# Generated by FakeRAM 2.0
VERSION 5.7 ;
BUSBITCHARS "[]" ;
PROPERTYDEFINITIONS
  MACRO width INTEGER ;
  MACRO depth INTEGER ;
  MACRO banks INTEGER ;
END PROPERTYDEFINITIONS
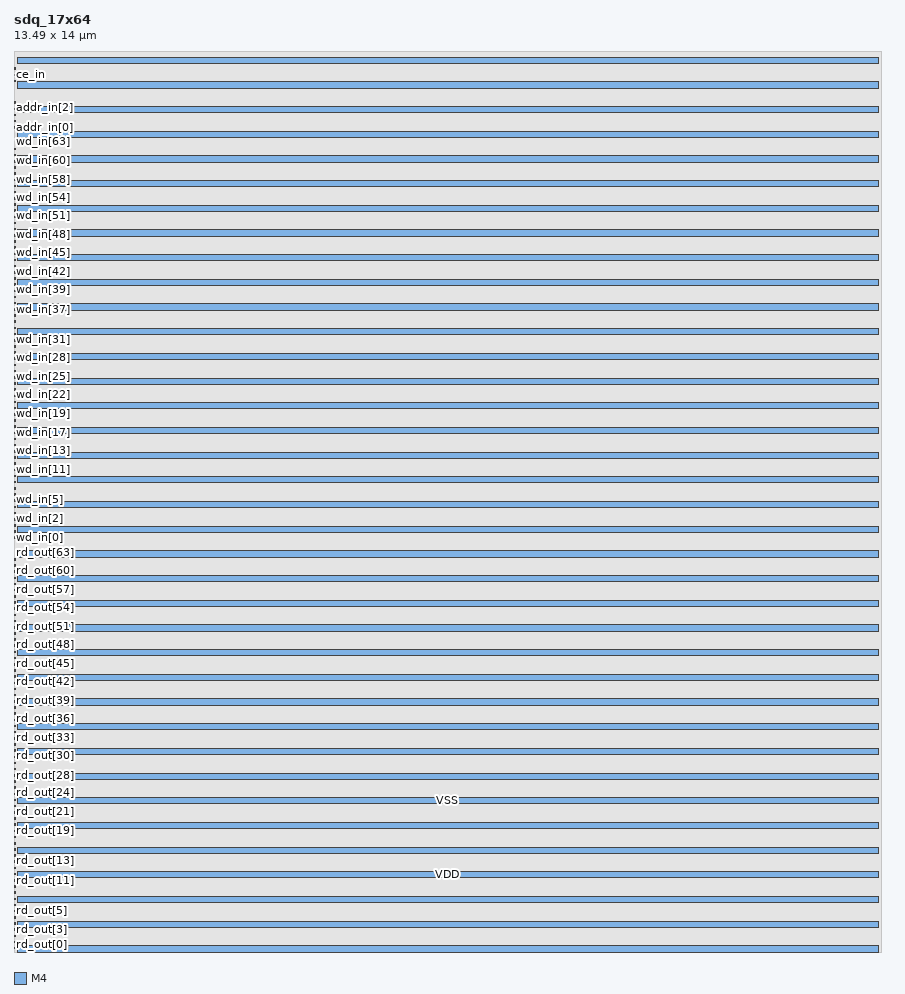
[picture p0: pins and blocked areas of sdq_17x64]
MACRO sdq_17x64
  PROPERTY width 64 ;
  PROPERTY depth 17 ;
  PROPERTY banks 1 ;
  FOREIGN sdq_17x64 0 0 ;
  SYMMETRY X Y R90 ;
  SIZE 13.490 BY 14.000 ;
  CLASS BLOCK ;
  PIN rd_out[0]
    DIRECTION OUTPUT ;
    USE SIGNAL ;
    SHAPE ABUTMENT ;
    PORT
      LAYER M4 ;
      RECT 0.000 0.048 0.024 0.072 ;
    END
  END rd_out[0]
  PIN rd_out[1]
    DIRECTION OUTPUT ;
    USE SIGNAL ;
    SHAPE ABUTMENT ;
    PORT
      LAYER M4 ;
      RECT 0.000 0.144 0.024 0.168 ;
    END
  END rd_out[1]
  PIN rd_out[2]
    DIRECTION OUTPUT ;
    USE SIGNAL ;
    SHAPE ABUTMENT ;
    PORT
      LAYER M4 ;
      RECT 0.000 0.240 0.024 0.264 ;
    END
  END rd_out[2]
  PIN rd_out[3]
    DIRECTION OUTPUT ;
    USE SIGNAL ;
    SHAPE ABUTMENT ;
    PORT
      LAYER M4 ;
      RECT 0.000 0.336 0.024 0.360 ;
    END
  END rd_out[3]
  PIN rd_out[4]
    DIRECTION OUTPUT ;
    USE SIGNAL ;
    SHAPE ABUTMENT ;
    PORT
      LAYER M4 ;
      RECT 0.000 0.432 0.024 0.456 ;
    END
  END rd_out[4]
  PIN rd_out[5]
    DIRECTION OUTPUT ;
    USE SIGNAL ;
    SHAPE ABUTMENT ;
    PORT
      LAYER M4 ;
      RECT 0.000 0.528 0.024 0.552 ;
    END
  END rd_out[5]
  PIN rd_out[6]
    DIRECTION OUTPUT ;
    USE SIGNAL ;
    SHAPE ABUTMENT ;
    PORT
      LAYER M4 ;
      RECT 0.000 0.624 0.024 0.648 ;
    END
  END rd_out[6]
  PIN rd_out[7]
    DIRECTION OUTPUT ;
    USE SIGNAL ;
    SHAPE ABUTMENT ;
    PORT
      LAYER M4 ;
      RECT 0.000 0.720 0.024 0.744 ;
    END
  END rd_out[7]
  PIN rd_out[8]
    DIRECTION OUTPUT ;
    USE SIGNAL ;
    SHAPE ABUTMENT ;
    PORT
      LAYER M4 ;
      RECT 0.000 0.816 0.024 0.840 ;
    END
  END rd_out[8]
  PIN rd_out[9]
    DIRECTION OUTPUT ;
    USE SIGNAL ;
    SHAPE ABUTMENT ;
    PORT
      LAYER M4 ;
      RECT 0.000 0.912 0.024 0.936 ;
    END
  END rd_out[9]
  PIN rd_out[10]
    DIRECTION OUTPUT ;
    USE SIGNAL ;
    SHAPE ABUTMENT ;
    PORT
      LAYER M4 ;
      RECT 0.000 1.008 0.024 1.032 ;
    END
  END rd_out[10]
  PIN rd_out[11]
    DIRECTION OUTPUT ;
    USE SIGNAL ;
    SHAPE ABUTMENT ;
    PORT
      LAYER M4 ;
      RECT 0.000 1.104 0.024 1.128 ;
    END
  END rd_out[11]
  PIN rd_out[12]
    DIRECTION OUTPUT ;
    USE SIGNAL ;
    SHAPE ABUTMENT ;
    PORT
      LAYER M4 ;
      RECT 0.000 1.200 0.024 1.224 ;
    END
  END rd_out[12]
  PIN rd_out[13]
    DIRECTION OUTPUT ;
    USE SIGNAL ;
    SHAPE ABUTMENT ;
    PORT
      LAYER M4 ;
      RECT 0.000 1.296 0.024 1.320 ;
    END
  END rd_out[13]
  PIN rd_out[14]
    DIRECTION OUTPUT ;
    USE SIGNAL ;
    SHAPE ABUTMENT ;
    PORT
      LAYER M4 ;
      RECT 0.000 1.392 0.024 1.416 ;
    END
  END rd_out[14]
  PIN rd_out[15]
    DIRECTION OUTPUT ;
    USE SIGNAL ;
    SHAPE ABUTMENT ;
    PORT
      LAYER M4 ;
      RECT 0.000 1.488 0.024 1.512 ;
    END
  END rd_out[15]
  PIN rd_out[16]
    DIRECTION OUTPUT ;
    USE SIGNAL ;
    SHAPE ABUTMENT ;
    PORT
      LAYER M4 ;
      RECT 0.000 1.584 0.024 1.608 ;
    END
  END rd_out[16]
  PIN rd_out[17]
    DIRECTION OUTPUT ;
    USE SIGNAL ;
    SHAPE ABUTMENT ;
    PORT
      LAYER M4 ;
      RECT 0.000 1.680 0.024 1.704 ;
    END
  END rd_out[17]
  PIN rd_out[18]
    DIRECTION OUTPUT ;
    USE SIGNAL ;
    SHAPE ABUTMENT ;
    PORT
      LAYER M4 ;
      RECT 0.000 1.776 0.024 1.800 ;
    END
  END rd_out[18]
  PIN rd_out[19]
    DIRECTION OUTPUT ;
    USE SIGNAL ;
    SHAPE ABUTMENT ;
    PORT
      LAYER M4 ;
      RECT 0.000 1.872 0.024 1.896 ;
    END
  END rd_out[19]
  PIN rd_out[20]
    DIRECTION OUTPUT ;
    USE SIGNAL ;
    SHAPE ABUTMENT ;
    PORT
      LAYER M4 ;
      RECT 0.000 1.968 0.024 1.992 ;
    END
  END rd_out[20]
  PIN rd_out[21]
    DIRECTION OUTPUT ;
    USE SIGNAL ;
    SHAPE ABUTMENT ;
    PORT
      LAYER M4 ;
      RECT 0.000 2.064 0.024 2.088 ;
    END
  END rd_out[21]
  PIN rd_out[22]
    DIRECTION OUTPUT ;
    USE SIGNAL ;
    SHAPE ABUTMENT ;
    PORT
      LAYER M4 ;
      RECT 0.000 2.160 0.024 2.184 ;
    END
  END rd_out[22]
  PIN rd_out[23]
    DIRECTION OUTPUT ;
    USE SIGNAL ;
    SHAPE ABUTMENT ;
    PORT
      LAYER M4 ;
      RECT 0.000 2.256 0.024 2.280 ;
    END
  END rd_out[23]
  PIN rd_out[24]
    DIRECTION OUTPUT ;
    USE SIGNAL ;
    SHAPE ABUTMENT ;
    PORT
      LAYER M4 ;
      RECT 0.000 2.352 0.024 2.376 ;
    END
  END rd_out[24]
  PIN rd_out[25]
    DIRECTION OUTPUT ;
    USE SIGNAL ;
    SHAPE ABUTMENT ;
    PORT
      LAYER M4 ;
      RECT 0.000 2.448 0.024 2.472 ;
    END
  END rd_out[25]
  PIN rd_out[26]
    DIRECTION OUTPUT ;
    USE SIGNAL ;
    SHAPE ABUTMENT ;
    PORT
      LAYER M4 ;
      RECT 0.000 2.544 0.024 2.568 ;
    END
  END rd_out[26]
  PIN rd_out[27]
    DIRECTION OUTPUT ;
    USE SIGNAL ;
    SHAPE ABUTMENT ;
    PORT
      LAYER M4 ;
      RECT 0.000 2.640 0.024 2.664 ;
    END
  END rd_out[27]
  PIN rd_out[28]
    DIRECTION OUTPUT ;
    USE SIGNAL ;
    SHAPE ABUTMENT ;
    PORT
      LAYER M4 ;
      RECT 0.000 2.736 0.024 2.760 ;
    END
  END rd_out[28]
  PIN rd_out[29]
    DIRECTION OUTPUT ;
    USE SIGNAL ;
    SHAPE ABUTMENT ;
    PORT
      LAYER M4 ;
      RECT 0.000 2.832 0.024 2.856 ;
    END
  END rd_out[29]
  PIN rd_out[30]
    DIRECTION OUTPUT ;
    USE SIGNAL ;
    SHAPE ABUTMENT ;
    PORT
      LAYER M4 ;
      RECT 0.000 2.928 0.024 2.952 ;
    END
  END rd_out[30]
  PIN rd_out[31]
    DIRECTION OUTPUT ;
    USE SIGNAL ;
    SHAPE ABUTMENT ;
    PORT
      LAYER M4 ;
      RECT 0.000 3.024 0.024 3.048 ;
    END
  END rd_out[31]
  PIN rd_out[32]
    DIRECTION OUTPUT ;
    USE SIGNAL ;
    SHAPE ABUTMENT ;
    PORT
      LAYER M4 ;
      RECT 0.000 3.120 0.024 3.144 ;
    END
  END rd_out[32]
  PIN rd_out[33]
    DIRECTION OUTPUT ;
    USE SIGNAL ;
    SHAPE ABUTMENT ;
    PORT
      LAYER M4 ;
      RECT 0.000 3.216 0.024 3.240 ;
    END
  END rd_out[33]
  PIN rd_out[34]
    DIRECTION OUTPUT ;
    USE SIGNAL ;
    SHAPE ABUTMENT ;
    PORT
      LAYER M4 ;
      RECT 0.000 3.312 0.024 3.336 ;
    END
  END rd_out[34]
  PIN rd_out[35]
    DIRECTION OUTPUT ;
    USE SIGNAL ;
    SHAPE ABUTMENT ;
    PORT
      LAYER M4 ;
      RECT 0.000 3.408 0.024 3.432 ;
    END
  END rd_out[35]
  PIN rd_out[36]
    DIRECTION OUTPUT ;
    USE SIGNAL ;
    SHAPE ABUTMENT ;
    PORT
      LAYER M4 ;
      RECT 0.000 3.504 0.024 3.528 ;
    END
  END rd_out[36]
  PIN rd_out[37]
    DIRECTION OUTPUT ;
    USE SIGNAL ;
    SHAPE ABUTMENT ;
    PORT
      LAYER M4 ;
      RECT 0.000 3.600 0.024 3.624 ;
    END
  END rd_out[37]
  PIN rd_out[38]
    DIRECTION OUTPUT ;
    USE SIGNAL ;
    SHAPE ABUTMENT ;
    PORT
      LAYER M4 ;
      RECT 0.000 3.696 0.024 3.720 ;
    END
  END rd_out[38]
  PIN rd_out[39]
    DIRECTION OUTPUT ;
    USE SIGNAL ;
    SHAPE ABUTMENT ;
    PORT
      LAYER M4 ;
      RECT 0.000 3.792 0.024 3.816 ;
    END
  END rd_out[39]
  PIN rd_out[40]
    DIRECTION OUTPUT ;
    USE SIGNAL ;
    SHAPE ABUTMENT ;
    PORT
      LAYER M4 ;
      RECT 0.000 3.888 0.024 3.912 ;
    END
  END rd_out[40]
  PIN rd_out[41]
    DIRECTION OUTPUT ;
    USE SIGNAL ;
    SHAPE ABUTMENT ;
    PORT
      LAYER M4 ;
      RECT 0.000 3.984 0.024 4.008 ;
    END
  END rd_out[41]
  PIN rd_out[42]
    DIRECTION OUTPUT ;
    USE SIGNAL ;
    SHAPE ABUTMENT ;
    PORT
      LAYER M4 ;
      RECT 0.000 4.080 0.024 4.104 ;
    END
  END rd_out[42]
  PIN rd_out[43]
    DIRECTION OUTPUT ;
    USE SIGNAL ;
    SHAPE ABUTMENT ;
    PORT
      LAYER M4 ;
      RECT 0.000 4.176 0.024 4.200 ;
    END
  END rd_out[43]
  PIN rd_out[44]
    DIRECTION OUTPUT ;
    USE SIGNAL ;
    SHAPE ABUTMENT ;
    PORT
      LAYER M4 ;
      RECT 0.000 4.272 0.024 4.296 ;
    END
  END rd_out[44]
  PIN rd_out[45]
    DIRECTION OUTPUT ;
    USE SIGNAL ;
    SHAPE ABUTMENT ;
    PORT
      LAYER M4 ;
      RECT 0.000 4.368 0.024 4.392 ;
    END
  END rd_out[45]
  PIN rd_out[46]
    DIRECTION OUTPUT ;
    USE SIGNAL ;
    SHAPE ABUTMENT ;
    PORT
      LAYER M4 ;
      RECT 0.000 4.464 0.024 4.488 ;
    END
  END rd_out[46]
  PIN rd_out[47]
    DIRECTION OUTPUT ;
    USE SIGNAL ;
    SHAPE ABUTMENT ;
    PORT
      LAYER M4 ;
      RECT 0.000 4.560 0.024 4.584 ;
    END
  END rd_out[47]
  PIN rd_out[48]
    DIRECTION OUTPUT ;
    USE SIGNAL ;
    SHAPE ABUTMENT ;
    PORT
      LAYER M4 ;
      RECT 0.000 4.656 0.024 4.680 ;
    END
  END rd_out[48]
  PIN rd_out[49]
    DIRECTION OUTPUT ;
    USE SIGNAL ;
    SHAPE ABUTMENT ;
    PORT
      LAYER M4 ;
      RECT 0.000 4.752 0.024 4.776 ;
    END
  END rd_out[49]
  PIN rd_out[50]
    DIRECTION OUTPUT ;
    USE SIGNAL ;
    SHAPE ABUTMENT ;
    PORT
      LAYER M4 ;
      RECT 0.000 4.848 0.024 4.872 ;
    END
  END rd_out[50]
  PIN rd_out[51]
    DIRECTION OUTPUT ;
    USE SIGNAL ;
    SHAPE ABUTMENT ;
    PORT
      LAYER M4 ;
      RECT 0.000 4.944 0.024 4.968 ;
    END
  END rd_out[51]
  PIN rd_out[52]
    DIRECTION OUTPUT ;
    USE SIGNAL ;
    SHAPE ABUTMENT ;
    PORT
      LAYER M4 ;
      RECT 0.000 5.040 0.024 5.064 ;
    END
  END rd_out[52]
  PIN rd_out[53]
    DIRECTION OUTPUT ;
    USE SIGNAL ;
    SHAPE ABUTMENT ;
    PORT
      LAYER M4 ;
      RECT 0.000 5.136 0.024 5.160 ;
    END
  END rd_out[53]
  PIN rd_out[54]
    DIRECTION OUTPUT ;
    USE SIGNAL ;
    SHAPE ABUTMENT ;
    PORT
      LAYER M4 ;
      RECT 0.000 5.232 0.024 5.256 ;
    END
  END rd_out[54]
  PIN rd_out[55]
    DIRECTION OUTPUT ;
    USE SIGNAL ;
    SHAPE ABUTMENT ;
    PORT
      LAYER M4 ;
      RECT 0.000 5.328 0.024 5.352 ;
    END
  END rd_out[55]
  PIN rd_out[56]
    DIRECTION OUTPUT ;
    USE SIGNAL ;
    SHAPE ABUTMENT ;
    PORT
      LAYER M4 ;
      RECT 0.000 5.424 0.024 5.448 ;
    END
  END rd_out[56]
  PIN rd_out[57]
    DIRECTION OUTPUT ;
    USE SIGNAL ;
    SHAPE ABUTMENT ;
    PORT
      LAYER M4 ;
      RECT 0.000 5.520 0.024 5.544 ;
    END
  END rd_out[57]
  PIN rd_out[58]
    DIRECTION OUTPUT ;
    USE SIGNAL ;
    SHAPE ABUTMENT ;
    PORT
      LAYER M4 ;
      RECT 0.000 5.616 0.024 5.640 ;
    END
  END rd_out[58]
  PIN rd_out[59]
    DIRECTION OUTPUT ;
    USE SIGNAL ;
    SHAPE ABUTMENT ;
    PORT
      LAYER M4 ;
      RECT 0.000 5.712 0.024 5.736 ;
    END
  END rd_out[59]
  PIN rd_out[60]
    DIRECTION OUTPUT ;
    USE SIGNAL ;
    SHAPE ABUTMENT ;
    PORT
      LAYER M4 ;
      RECT 0.000 5.808 0.024 5.832 ;
    END
  END rd_out[60]
  PIN rd_out[61]
    DIRECTION OUTPUT ;
    USE SIGNAL ;
    SHAPE ABUTMENT ;
    PORT
      LAYER M4 ;
      RECT 0.000 5.904 0.024 5.928 ;
    END
  END rd_out[61]
  PIN rd_out[62]
    DIRECTION OUTPUT ;
    USE SIGNAL ;
    SHAPE ABUTMENT ;
    PORT
      LAYER M4 ;
      RECT 0.000 6.000 0.024 6.024 ;
    END
  END rd_out[62]
  PIN rd_out[63]
    DIRECTION OUTPUT ;
    USE SIGNAL ;
    SHAPE ABUTMENT ;
    PORT
      LAYER M4 ;
      RECT 0.000 6.096 0.024 6.120 ;
    END
  END rd_out[63]
  PIN wd_in[0]
    DIRECTION INPUT ;
    USE SIGNAL ;
    SHAPE ABUTMENT ;
    PORT
      LAYER M4 ;
      RECT 0.000 6.432 0.024 6.456 ;
    END
  END wd_in[0]
  PIN wd_in[1]
    DIRECTION INPUT ;
    USE SIGNAL ;
    SHAPE ABUTMENT ;
    PORT
      LAYER M4 ;
      RECT 0.000 6.528 0.024 6.552 ;
    END
  END wd_in[1]
  PIN wd_in[2]
    DIRECTION INPUT ;
    USE SIGNAL ;
    SHAPE ABUTMENT ;
    PORT
      LAYER M4 ;
      RECT 0.000 6.624 0.024 6.648 ;
    END
  END wd_in[2]
  PIN wd_in[3]
    DIRECTION INPUT ;
    USE SIGNAL ;
    SHAPE ABUTMENT ;
    PORT
      LAYER M4 ;
      RECT 0.000 6.720 0.024 6.744 ;
    END
  END wd_in[3]
  PIN wd_in[4]
    DIRECTION INPUT ;
    USE SIGNAL ;
    SHAPE ABUTMENT ;
    PORT
      LAYER M4 ;
      RECT 0.000 6.816 0.024 6.840 ;
    END
  END wd_in[4]
  PIN wd_in[5]
    DIRECTION INPUT ;
    USE SIGNAL ;
    SHAPE ABUTMENT ;
    PORT
      LAYER M4 ;
      RECT 0.000 6.912 0.024 6.936 ;
    END
  END wd_in[5]
  PIN wd_in[6]
    DIRECTION INPUT ;
    USE SIGNAL ;
    SHAPE ABUTMENT ;
    PORT
      LAYER M4 ;
      RECT 0.000 7.008 0.024 7.032 ;
    END
  END wd_in[6]
  PIN wd_in[7]
    DIRECTION INPUT ;
    USE SIGNAL ;
    SHAPE ABUTMENT ;
    PORT
      LAYER M4 ;
      RECT 0.000 7.104 0.024 7.128 ;
    END
  END wd_in[7]
  PIN wd_in[8]
    DIRECTION INPUT ;
    USE SIGNAL ;
    SHAPE ABUTMENT ;
    PORT
      LAYER M4 ;
      RECT 0.000 7.200 0.024 7.224 ;
    END
  END wd_in[8]
  PIN wd_in[9]
    DIRECTION INPUT ;
    USE SIGNAL ;
    SHAPE ABUTMENT ;
    PORT
      LAYER M4 ;
      RECT 0.000 7.296 0.024 7.320 ;
    END
  END wd_in[9]
  PIN wd_in[10]
    DIRECTION INPUT ;
    USE SIGNAL ;
    SHAPE ABUTMENT ;
    PORT
      LAYER M4 ;
      RECT 0.000 7.392 0.024 7.416 ;
    END
  END wd_in[10]
  PIN wd_in[11]
    DIRECTION INPUT ;
    USE SIGNAL ;
    SHAPE ABUTMENT ;
    PORT
      LAYER M4 ;
      RECT 0.000 7.488 0.024 7.512 ;
    END
  END wd_in[11]
  PIN wd_in[12]
    DIRECTION INPUT ;
    USE SIGNAL ;
    SHAPE ABUTMENT ;
    PORT
      LAYER M4 ;
      RECT 0.000 7.584 0.024 7.608 ;
    END
  END wd_in[12]
  PIN wd_in[13]
    DIRECTION INPUT ;
    USE SIGNAL ;
    SHAPE ABUTMENT ;
    PORT
      LAYER M4 ;
      RECT 0.000 7.680 0.024 7.704 ;
    END
  END wd_in[13]
  PIN wd_in[14]
    DIRECTION INPUT ;
    USE SIGNAL ;
    SHAPE ABUTMENT ;
    PORT
      LAYER M4 ;
      RECT 0.000 7.776 0.024 7.800 ;
    END
  END wd_in[14]
  PIN wd_in[15]
    DIRECTION INPUT ;
    USE SIGNAL ;
    SHAPE ABUTMENT ;
    PORT
      LAYER M4 ;
      RECT 0.000 7.872 0.024 7.896 ;
    END
  END wd_in[15]
  PIN wd_in[16]
    DIRECTION INPUT ;
    USE SIGNAL ;
    SHAPE ABUTMENT ;
    PORT
      LAYER M4 ;
      RECT 0.000 7.968 0.024 7.992 ;
    END
  END wd_in[16]
  PIN wd_in[17]
    DIRECTION INPUT ;
    USE SIGNAL ;
    SHAPE ABUTMENT ;
    PORT
      LAYER M4 ;
      RECT 0.000 8.064 0.024 8.088 ;
    END
  END wd_in[17]
  PIN wd_in[18]
    DIRECTION INPUT ;
    USE SIGNAL ;
    SHAPE ABUTMENT ;
    PORT
      LAYER M4 ;
      RECT 0.000 8.160 0.024 8.184 ;
    END
  END wd_in[18]
  PIN wd_in[19]
    DIRECTION INPUT ;
    USE SIGNAL ;
    SHAPE ABUTMENT ;
    PORT
      LAYER M4 ;
      RECT 0.000 8.256 0.024 8.280 ;
    END
  END wd_in[19]
  PIN wd_in[20]
    DIRECTION INPUT ;
    USE SIGNAL ;
    SHAPE ABUTMENT ;
    PORT
      LAYER M4 ;
      RECT 0.000 8.352 0.024 8.376 ;
    END
  END wd_in[20]
  PIN wd_in[21]
    DIRECTION INPUT ;
    USE SIGNAL ;
    SHAPE ABUTMENT ;
    PORT
      LAYER M4 ;
      RECT 0.000 8.448 0.024 8.472 ;
    END
  END wd_in[21]
  PIN wd_in[22]
    DIRECTION INPUT ;
    USE SIGNAL ;
    SHAPE ABUTMENT ;
    PORT
      LAYER M4 ;
      RECT 0.000 8.544 0.024 8.568 ;
    END
  END wd_in[22]
  PIN wd_in[23]
    DIRECTION INPUT ;
    USE SIGNAL ;
    SHAPE ABUTMENT ;
    PORT
      LAYER M4 ;
      RECT 0.000 8.640 0.024 8.664 ;
    END
  END wd_in[23]
  PIN wd_in[24]
    DIRECTION INPUT ;
    USE SIGNAL ;
    SHAPE ABUTMENT ;
    PORT
      LAYER M4 ;
      RECT 0.000 8.736 0.024 8.760 ;
    END
  END wd_in[24]
  PIN wd_in[25]
    DIRECTION INPUT ;
    USE SIGNAL ;
    SHAPE ABUTMENT ;
    PORT
      LAYER M4 ;
      RECT 0.000 8.832 0.024 8.856 ;
    END
  END wd_in[25]
  PIN wd_in[26]
    DIRECTION INPUT ;
    USE SIGNAL ;
    SHAPE ABUTMENT ;
    PORT
      LAYER M4 ;
      RECT 0.000 8.928 0.024 8.952 ;
    END
  END wd_in[26]
  PIN wd_in[27]
    DIRECTION INPUT ;
    USE SIGNAL ;
    SHAPE ABUTMENT ;
    PORT
      LAYER M4 ;
      RECT 0.000 9.024 0.024 9.048 ;
    END
  END wd_in[27]
  PIN wd_in[28]
    DIRECTION INPUT ;
    USE SIGNAL ;
    SHAPE ABUTMENT ;
    PORT
      LAYER M4 ;
      RECT 0.000 9.120 0.024 9.144 ;
    END
  END wd_in[28]
  PIN wd_in[29]
    DIRECTION INPUT ;
    USE SIGNAL ;
    SHAPE ABUTMENT ;
    PORT
      LAYER M4 ;
      RECT 0.000 9.216 0.024 9.240 ;
    END
  END wd_in[29]
  PIN wd_in[30]
    DIRECTION INPUT ;
    USE SIGNAL ;
    SHAPE ABUTMENT ;
    PORT
      LAYER M4 ;
      RECT 0.000 9.312 0.024 9.336 ;
    END
  END wd_in[30]
  PIN wd_in[31]
    DIRECTION INPUT ;
    USE SIGNAL ;
    SHAPE ABUTMENT ;
    PORT
      LAYER M4 ;
      RECT 0.000 9.408 0.024 9.432 ;
    END
  END wd_in[31]
  PIN wd_in[32]
    DIRECTION INPUT ;
    USE SIGNAL ;
    SHAPE ABUTMENT ;
    PORT
      LAYER M4 ;
      RECT 0.000 9.504 0.024 9.528 ;
    END
  END wd_in[32]
  PIN wd_in[33]
    DIRECTION INPUT ;
    USE SIGNAL ;
    SHAPE ABUTMENT ;
    PORT
      LAYER M4 ;
      RECT 0.000 9.600 0.024 9.624 ;
    END
  END wd_in[33]
  PIN wd_in[34]
    DIRECTION INPUT ;
    USE SIGNAL ;
    SHAPE ABUTMENT ;
    PORT
      LAYER M4 ;
      RECT 0.000 9.696 0.024 9.720 ;
    END
  END wd_in[34]
  PIN wd_in[35]
    DIRECTION INPUT ;
    USE SIGNAL ;
    SHAPE ABUTMENT ;
    PORT
      LAYER M4 ;
      RECT 0.000 9.792 0.024 9.816 ;
    END
  END wd_in[35]
  PIN wd_in[36]
    DIRECTION INPUT ;
    USE SIGNAL ;
    SHAPE ABUTMENT ;
    PORT
      LAYER M4 ;
      RECT 0.000 9.888 0.024 9.912 ;
    END
  END wd_in[36]
  PIN wd_in[37]
    DIRECTION INPUT ;
    USE SIGNAL ;
    SHAPE ABUTMENT ;
    PORT
      LAYER M4 ;
      RECT 0.000 9.984 0.024 10.008 ;
    END
  END wd_in[37]
  PIN wd_in[38]
    DIRECTION INPUT ;
    USE SIGNAL ;
    SHAPE ABUTMENT ;
    PORT
      LAYER M4 ;
      RECT 0.000 10.080 0.024 10.104 ;
    END
  END wd_in[38]
  PIN wd_in[39]
    DIRECTION INPUT ;
    USE SIGNAL ;
    SHAPE ABUTMENT ;
    PORT
      LAYER M4 ;
      RECT 0.000 10.176 0.024 10.200 ;
    END
  END wd_in[39]
  PIN wd_in[40]
    DIRECTION INPUT ;
    USE SIGNAL ;
    SHAPE ABUTMENT ;
    PORT
      LAYER M4 ;
      RECT 0.000 10.272 0.024 10.296 ;
    END
  END wd_in[40]
  PIN wd_in[41]
    DIRECTION INPUT ;
    USE SIGNAL ;
    SHAPE ABUTMENT ;
    PORT
      LAYER M4 ;
      RECT 0.000 10.368 0.024 10.392 ;
    END
  END wd_in[41]
  PIN wd_in[42]
    DIRECTION INPUT ;
    USE SIGNAL ;
    SHAPE ABUTMENT ;
    PORT
      LAYER M4 ;
      RECT 0.000 10.464 0.024 10.488 ;
    END
  END wd_in[42]
  PIN wd_in[43]
    DIRECTION INPUT ;
    USE SIGNAL ;
    SHAPE ABUTMENT ;
    PORT
      LAYER M4 ;
      RECT 0.000 10.560 0.024 10.584 ;
    END
  END wd_in[43]
  PIN wd_in[44]
    DIRECTION INPUT ;
    USE SIGNAL ;
    SHAPE ABUTMENT ;
    PORT
      LAYER M4 ;
      RECT 0.000 10.656 0.024 10.680 ;
    END
  END wd_in[44]
  PIN wd_in[45]
    DIRECTION INPUT ;
    USE SIGNAL ;
    SHAPE ABUTMENT ;
    PORT
      LAYER M4 ;
      RECT 0.000 10.752 0.024 10.776 ;
    END
  END wd_in[45]
  PIN wd_in[46]
    DIRECTION INPUT ;
    USE SIGNAL ;
    SHAPE ABUTMENT ;
    PORT
      LAYER M4 ;
      RECT 0.000 10.848 0.024 10.872 ;
    END
  END wd_in[46]
  PIN wd_in[47]
    DIRECTION INPUT ;
    USE SIGNAL ;
    SHAPE ABUTMENT ;
    PORT
      LAYER M4 ;
      RECT 0.000 10.944 0.024 10.968 ;
    END
  END wd_in[47]
  PIN wd_in[48]
    DIRECTION INPUT ;
    USE SIGNAL ;
    SHAPE ABUTMENT ;
    PORT
      LAYER M4 ;
      RECT 0.000 11.040 0.024 11.064 ;
    END
  END wd_in[48]
  PIN wd_in[49]
    DIRECTION INPUT ;
    USE SIGNAL ;
    SHAPE ABUTMENT ;
    PORT
      LAYER M4 ;
      RECT 0.000 11.136 0.024 11.160 ;
    END
  END wd_in[49]
  PIN wd_in[50]
    DIRECTION INPUT ;
    USE SIGNAL ;
    SHAPE ABUTMENT ;
    PORT
      LAYER M4 ;
      RECT 0.000 11.232 0.024 11.256 ;
    END
  END wd_in[50]
  PIN wd_in[51]
    DIRECTION INPUT ;
    USE SIGNAL ;
    SHAPE ABUTMENT ;
    PORT
      LAYER M4 ;
      RECT 0.000 11.328 0.024 11.352 ;
    END
  END wd_in[51]
  PIN wd_in[52]
    DIRECTION INPUT ;
    USE SIGNAL ;
    SHAPE ABUTMENT ;
    PORT
      LAYER M4 ;
      RECT 0.000 11.424 0.024 11.448 ;
    END
  END wd_in[52]
  PIN wd_in[53]
    DIRECTION INPUT ;
    USE SIGNAL ;
    SHAPE ABUTMENT ;
    PORT
      LAYER M4 ;
      RECT 0.000 11.520 0.024 11.544 ;
    END
  END wd_in[53]
  PIN wd_in[54]
    DIRECTION INPUT ;
    USE SIGNAL ;
    SHAPE ABUTMENT ;
    PORT
      LAYER M4 ;
      RECT 0.000 11.616 0.024 11.640 ;
    END
  END wd_in[54]
  PIN wd_in[55]
    DIRECTION INPUT ;
    USE SIGNAL ;
    SHAPE ABUTMENT ;
    PORT
      LAYER M4 ;
      RECT 0.000 11.712 0.024 11.736 ;
    END
  END wd_in[55]
  PIN wd_in[56]
    DIRECTION INPUT ;
    USE SIGNAL ;
    SHAPE ABUTMENT ;
    PORT
      LAYER M4 ;
      RECT 0.000 11.808 0.024 11.832 ;
    END
  END wd_in[56]
  PIN wd_in[57]
    DIRECTION INPUT ;
    USE SIGNAL ;
    SHAPE ABUTMENT ;
    PORT
      LAYER M4 ;
      RECT 0.000 11.904 0.024 11.928 ;
    END
  END wd_in[57]
  PIN wd_in[58]
    DIRECTION INPUT ;
    USE SIGNAL ;
    SHAPE ABUTMENT ;
    PORT
      LAYER M4 ;
      RECT 0.000 12.000 0.024 12.024 ;
    END
  END wd_in[58]
  PIN wd_in[59]
    DIRECTION INPUT ;
    USE SIGNAL ;
    SHAPE ABUTMENT ;
    PORT
      LAYER M4 ;
      RECT 0.000 12.096 0.024 12.120 ;
    END
  END wd_in[59]
  PIN wd_in[60]
    DIRECTION INPUT ;
    USE SIGNAL ;
    SHAPE ABUTMENT ;
    PORT
      LAYER M4 ;
      RECT 0.000 12.192 0.024 12.216 ;
    END
  END wd_in[60]
  PIN wd_in[61]
    DIRECTION INPUT ;
    USE SIGNAL ;
    SHAPE ABUTMENT ;
    PORT
      LAYER M4 ;
      RECT 0.000 12.288 0.024 12.312 ;
    END
  END wd_in[61]
  PIN wd_in[62]
    DIRECTION INPUT ;
    USE SIGNAL ;
    SHAPE ABUTMENT ;
    PORT
      LAYER M4 ;
      RECT 0.000 12.384 0.024 12.408 ;
    END
  END wd_in[62]
  PIN wd_in[63]
    DIRECTION INPUT ;
    USE SIGNAL ;
    SHAPE ABUTMENT ;
    PORT
      LAYER M4 ;
      RECT 0.000 12.480 0.024 12.504 ;
    END
  END wd_in[63]
  PIN addr_in[0]
    DIRECTION INPUT ;
    USE SIGNAL ;
    SHAPE ABUTMENT ;
    PORT
      LAYER M4 ;
      RECT 0.000 12.816 0.024 12.840 ;
    END
  END addr_in[0]
  PIN addr_in[1]
    DIRECTION INPUT ;
    USE SIGNAL ;
    SHAPE ABUTMENT ;
    PORT
      LAYER M4 ;
      RECT 0.000 12.912 0.024 12.936 ;
    END
  END addr_in[1]
  PIN addr_in[2]
    DIRECTION INPUT ;
    USE SIGNAL ;
    SHAPE ABUTMENT ;
    PORT
      LAYER M4 ;
      RECT 0.000 13.008 0.024 13.032 ;
    END
  END addr_in[2]
  PIN addr_in[3]
    DIRECTION INPUT ;
    USE SIGNAL ;
    SHAPE ABUTMENT ;
    PORT
      LAYER M4 ;
      RECT 0.000 13.104 0.024 13.128 ;
    END
  END addr_in[3]
  PIN addr_in[4]
    DIRECTION INPUT ;
    USE SIGNAL ;
    SHAPE ABUTMENT ;
    PORT
      LAYER M4 ;
      RECT 0.000 13.200 0.024 13.224 ;
    END
  END addr_in[4]
  PIN we_in
    DIRECTION INPUT ;
    USE SIGNAL ;
    SHAPE ABUTMENT ;
    PORT
      LAYER M4 ;
      RECT 0.000 13.536 0.024 13.560 ;
    END
  END we_in
  PIN ce_in
    DIRECTION INPUT ;
    USE SIGNAL ;
    SHAPE ABUTMENT ;
    PORT
      LAYER M4 ;
      RECT 0.000 13.632 0.024 13.656 ;
    END
  END ce_in
  PIN clk
    DIRECTION INPUT ;
    USE SIGNAL ;
    SHAPE ABUTMENT ;
    PORT
      LAYER M4 ;
      RECT 0.000 13.728 0.024 13.752 ;
    END
  END clk
  PIN VSS
    DIRECTION INOUT ;
    USE GROUND ;
    PORT
      LAYER M4 ;
      RECT 0.048 0.000 13.442 0.096 ;
      RECT 0.048 0.768 13.442 0.864 ;
      RECT 0.048 1.536 13.442 1.632 ;
      RECT 0.048 2.304 13.442 2.400 ;
      RECT 0.048 3.072 13.442 3.168 ;
      RECT 0.048 3.840 13.442 3.936 ;
      RECT 0.048 4.608 13.442 4.704 ;
      RECT 0.048 5.376 13.442 5.472 ;
      RECT 0.048 6.144 13.442 6.240 ;
      RECT 0.048 6.912 13.442 7.008 ;
      RECT 0.048 7.680 13.442 7.776 ;
      RECT 0.048 8.448 13.442 8.544 ;
      RECT 0.048 9.216 13.442 9.312 ;
      RECT 0.048 9.984 13.442 10.080 ;
      RECT 0.048 10.752 13.442 10.848 ;
      RECT 0.048 11.520 13.442 11.616 ;
      RECT 0.048 12.288 13.442 12.384 ;
      RECT 0.048 13.056 13.442 13.152 ;
      RECT 0.048 13.824 13.442 13.920 ;
    END
  END VSS
  PIN VDD
    DIRECTION INOUT ;
    USE POWER ;
    PORT
      LAYER M4 ;
      RECT 0.048 0.384 13.442 0.480 ;
      RECT 0.048 1.152 13.442 1.248 ;
      RECT 0.048 1.920 13.442 2.016 ;
      RECT 0.048 2.688 13.442 2.784 ;
      RECT 0.048 3.456 13.442 3.552 ;
      RECT 0.048 4.224 13.442 4.320 ;
      RECT 0.048 4.992 13.442 5.088 ;
      RECT 0.048 5.760 13.442 5.856 ;
      RECT 0.048 6.528 13.442 6.624 ;
      RECT 0.048 7.296 13.442 7.392 ;
      RECT 0.048 8.064 13.442 8.160 ;
      RECT 0.048 8.832 13.442 8.928 ;
      RECT 0.048 9.600 13.442 9.696 ;
      RECT 0.048 10.368 13.442 10.464 ;
      RECT 0.048 11.136 13.442 11.232 ;
      RECT 0.048 11.904 13.442 12.000 ;
      RECT 0.048 12.672 13.442 12.768 ;
      RECT 0.048 13.440 13.442 13.536 ;
    END
  END VDD
  OBS
    LAYER M1 ;
    RECT 0 0 13.490 14.000 ;
    LAYER M2 ;
    RECT 0 0 13.490 14.000 ;
    LAYER M3 ;
    RECT 0 0 13.490 14.000 ;
    LAYER M4 ;
    RECT 0 0 13.490 14.000 ;
  END
END sdq_17x64

END LIBRARY
